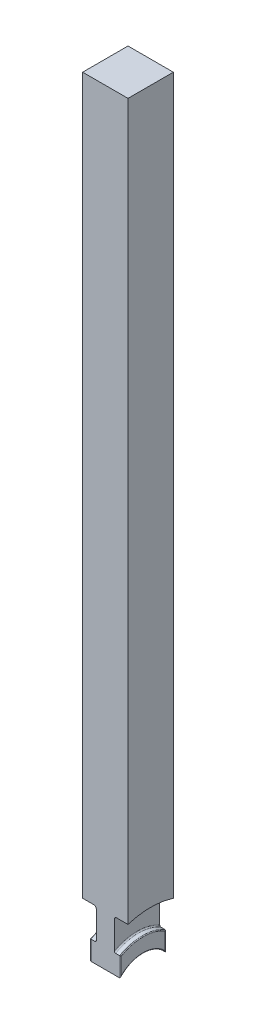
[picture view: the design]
ISO-10303-21;
HEADER;
FILE_DESCRIPTION(('STEP AP214'),'2;1');
FILE_NAME('part.step','',(''),(''),'','','');
FILE_SCHEMA(('AUTOMOTIVE_DESIGN { 1 0 10303 214 1 1 1 1 }'));
ENDSEC;
DATA;
#1=APPLICATION_CONTEXT('core data for automotive mechanical design processes');
#2=APPLICATION_PROTOCOL_DEFINITION('international standard','automotive_design',2000,#1);
#3=PRODUCT_CONTEXT('',#1,'mechanical');
#4=PRODUCT('Part','Part','',(#3));
#5=PRODUCT_RELATED_PRODUCT_CATEGORY('part','',(#4));
#6=PRODUCT_DEFINITION_FORMATION('','',#4);
#7=PRODUCT_DEFINITION_CONTEXT('part definition',#1,'design');
#8=PRODUCT_DEFINITION('design','',#6,#7);
#9=PRODUCT_DEFINITION_SHAPE('','',#8);
#10=(LENGTH_UNIT() NAMED_UNIT(*) SI_UNIT(.MILLI.,.METRE.));
#11=(NAMED_UNIT(*) PLANE_ANGLE_UNIT() SI_UNIT($,.RADIAN.));
#12=(NAMED_UNIT(*) SI_UNIT($,.STERADIAN.) SOLID_ANGLE_UNIT());
#13=UNCERTAINTY_MEASURE_WITH_UNIT(LENGTH_MEASURE(1.E-05),#10,'distance_accuracy_value','');
#14=(GEOMETRIC_REPRESENTATION_CONTEXT(3) GLOBAL_UNCERTAINTY_ASSIGNED_CONTEXT((#13)) GLOBAL_UNIT_ASSIGNED_CONTEXT((#10,
#11,#12)) REPRESENTATION_CONTEXT('',''));
#15=CARTESIAN_POINT('',(0.,0.,0.));
#16=DIRECTION('',(0.,0.,1.));
#17=DIRECTION('',(1.,0.,0.));
#18=AXIS2_PLACEMENT_3D('',#15,#16,#17);
#19=CARTESIAN_POINT('',(7.5,260.,7.5));
#20=DIRECTION('',(0.,0.,-1.));
#21=DIRECTION('',(0.,1.,0.));
#22=AXIS2_PLACEMENT_3D('',#19,#20,#21);
#23=PLANE('',#22);
#24=DIRECTION('',(-1.,0.,0.));
#25=VECTOR('',#24,1.);
#26=CARTESIAN_POINT('',(-8.84822894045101,12.9903810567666,7.49999999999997));
#27=LINE('',#26,#25);
#28=CARTESIAN_POINT('',(-4.75,12.9903810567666,7.49999999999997));
#29=VERTEX_POINT('',#28);
#30=CARTESIAN_POINT('',(-3.381,12.9903810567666,7.49999999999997));
#31=VERTEX_POINT('',#30);
#32=EDGE_CURVE('E731',#29,#31,#27,.F.);
#33=ORIENTED_EDGE('',*,*,#32,.F.);
#34=DIRECTION('',(0.,1.,0.));
#35=VECTOR('',#34,1.);
#36=CARTESIAN_POINT('',(-4.75000000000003,260.,7.5));
#37=LINE('',#36,#35);
#38=CARTESIAN_POINT('',(-4.75,6.61437827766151,7.49999999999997));
#39=VERTEX_POINT('',#38);
#40=EDGE_CURVE('E442',#29,#39,#37,.F.);
#41=ORIENTED_EDGE('',*,*,#40,.T.);
#42=DIRECTION('',(1.,0.,0.));
#43=VECTOR('',#42,1.);
#44=CARTESIAN_POINT('',(-7.5,6.61437827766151,7.49999999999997));
#45=LINE('',#44,#43);
#46=CARTESIAN_POINT('',(4.75,6.61437827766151,7.49999999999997));
#47=VERTEX_POINT('',#46);
#48=EDGE_CURVE('E212',#39,#47,#45,.T.);
#49=ORIENTED_EDGE('',*,*,#48,.T.);
#50=DIRECTION('',(0.,-1.,0.));
#51=VECTOR('',#50,1.);
#52=CARTESIAN_POINT('',(4.74999999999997,260.,7.5));
#53=LINE('',#52,#51);
#54=CARTESIAN_POINT('',(4.75,12.9903810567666,7.49999999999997));
#55=VERTEX_POINT('',#54);
#56=EDGE_CURVE('E440',#47,#55,#53,.F.);
#57=ORIENTED_EDGE('',*,*,#56,.T.);
#58=DIRECTION('',(-1.,0.,0.));
#59=VECTOR('',#58,1.);
#60=CARTESIAN_POINT('',(-8.84822894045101,12.9903810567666,7.49999999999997));
#61=LINE('',#60,#59);
#62=CARTESIAN_POINT('',(3.381,12.9903810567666,7.49999999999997));
#63=VERTEX_POINT('',#62);
#64=EDGE_CURVE('E734',#63,#55,#61,.F.);
#65=ORIENTED_EDGE('',*,*,#64,.F.);
#66=CARTESIAN_POINT('',(3.381,12.9903810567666,7.49999999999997));
#67=CARTESIAN_POINT('',(3.36159348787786,12.990351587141,7.49999999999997));
#68=CARTESIAN_POINT('',(3.34220939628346,12.9920910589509,7.49999999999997));
#69=CARTESIAN_POINT('',(3.30411089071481,12.9988686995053,7.49999999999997));
#70=CARTESIAN_POINT('',(3.28539391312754,13.0038923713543,7.49999999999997));
#71=CARTESIAN_POINT('',(3.24909102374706,13.0169971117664,7.49999999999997));
#72=CARTESIAN_POINT('',(3.23150411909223,13.0250754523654,7.49999999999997));
#73=CARTESIAN_POINT('',(3.19783116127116,13.0439266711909,7.49999999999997));
#74=CARTESIAN_POINT('',(3.18174642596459,13.054701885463,7.49999999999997));
#75=CARTESIAN_POINT('',(3.15058262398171,13.0791681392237,7.49999999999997));
#76=CARTESIAN_POINT('',(3.1356009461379,13.0929827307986,7.49999999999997));
#77=CARTESIAN_POINT('',(3.10785285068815,13.1226713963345,7.49999999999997));
#78=CARTESIAN_POINT('',(3.09508691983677,13.1385459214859,7.49999999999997));
#79=CARTESIAN_POINT('',(3.07041818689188,13.1740413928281,7.49999999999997));
#80=CARTESIAN_POINT('',(3.05883169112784,13.1938820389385,7.49999999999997));
#81=CARTESIAN_POINT('',(3.03871875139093,13.235070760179,7.49999999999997));
#82=CARTESIAN_POINT('',(3.03019562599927,13.2564204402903,7.49999999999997));
#83=CARTESIAN_POINT('',(3.01549657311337,13.3025258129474,7.49999999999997));
#84=CARTESIAN_POINT('',(3.00968374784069,13.3273972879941,7.49999999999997));
#85=CARTESIAN_POINT('',(3.00193752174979,13.3776913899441,7.49999999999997));
#86=CARTESIAN_POINT('',(2.99999691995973,13.4031129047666,7.49999999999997));
#87=CARTESIAN_POINT('',(3.,13.428520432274,7.49999999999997));
#88=B_SPLINE_CURVE_WITH_KNOTS('',3,(#66,#67,#68,#69,#70,#71,#72,#73,#74,#75,#76,#77,#78,#79,#80,
#81,#82,#83,#84,#85,#86,#87),.UNSPECIFIED.,.F.,.F.,(4,2,2,2,2,2,2,2,2,2,4),(0.,
0.0581065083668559,0.115958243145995,0.173758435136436,0.231608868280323,0.292501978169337,
0.353408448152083,0.422061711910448,0.490789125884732,0.567105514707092,0.643279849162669),.UNSPECIFIED.);
#89=CARTESIAN_POINT('',(3.,13.428520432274,7.49999999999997));
#90=VERTEX_POINT('',#89);
#91=EDGE_CURVE('E312',#63,#90,#88,.T.);
#92=ORIENTED_EDGE('',*,*,#91,.T.);
#93=DIRECTION('',(0.,-1.,0.));
#94=VECTOR('',#93,1.);
#95=CARTESIAN_POINT('',(3.,260.,7.5));
#96=LINE('',#95,#94);
#97=CARTESIAN_POINT('',(3.,22.5220479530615,7.49999999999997));
#98=VERTEX_POINT('',#97);
#99=EDGE_CURVE('E464',#98,#90,#96,.T.);
#100=ORIENTED_EDGE('',*,*,#99,.F.);
#101=CARTESIAN_POINT('',(3.,22.5220479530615,7.49999999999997));
#102=CARTESIAN_POINT('',(2.99997149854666,22.5689651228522,7.49999999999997));
#103=CARTESIAN_POINT('',(3.00389939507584,22.6158879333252,7.49999999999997));
#104=CARTESIAN_POINT('',(3.01949238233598,22.7084725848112,7.49999999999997));
#105=CARTESIAN_POINT('',(3.03116447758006,22.754133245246,7.49999999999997));
#106=CARTESIAN_POINT('',(3.06208646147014,22.8428798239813,7.49999999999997));
#107=CARTESIAN_POINT('',(3.08134457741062,22.885962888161,7.49999999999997));
#108=CARTESIAN_POINT('',(3.12700930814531,22.9681343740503,7.49999999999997));
#109=CARTESIAN_POINT('',(3.15341113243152,23.0072254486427,7.49999999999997));
#110=CARTESIAN_POINT('',(3.21190757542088,23.0791064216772,7.49999999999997));
#111=CARTESIAN_POINT('',(3.24382440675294,23.1120407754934,7.49999999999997));
#112=CARTESIAN_POINT('',(3.31300016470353,23.171752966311,7.49999999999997));
#113=CARTESIAN_POINT('',(3.35025938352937,23.1985304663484,7.49999999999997));
#114=CARTESIAN_POINT('',(3.42707441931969,23.2437458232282,7.49999999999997));
#115=CARTESIAN_POINT('',(3.46642748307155,23.262528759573,7.49999999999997));
#116=CARTESIAN_POINT('',(3.54780361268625,23.2928652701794,7.49999999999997));
#117=CARTESIAN_POINT('',(3.58982304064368,23.3044284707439,7.49999999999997));
#118=CARTESIAN_POINT('',(3.65386676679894,23.3160362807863,7.49999999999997));
#119=CARTESIAN_POINT('',(3.67540624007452,23.3189494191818,7.49999999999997));
#120=CARTESIAN_POINT('',(3.71862671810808,23.322833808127,7.49999999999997));
#121=CARTESIAN_POINT('',(3.74030745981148,23.323807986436,7.49999999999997));
#122=CARTESIAN_POINT('',(3.76199999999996,23.3238075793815,7.49999999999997));
#123=B_SPLINE_CURVE_WITH_KNOTS('',3,(#101,#102,#103,#104,#105,#106,#107,#108,#109,#110,#111,
#112,#113,#114,#115,#116,#117,#118,#119,#120,#121,#122),.UNSPECIFIED.,.F.,.F.,(4,2,2,2,2,2,2,2,
2,2,4),(0.,0.140598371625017,0.281324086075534,0.422202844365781,0.562987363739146,
0.699875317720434,0.836770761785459,0.966940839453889,1.09693698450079,1.16206792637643,
1.22710044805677),.UNSPECIFIED.);
#124=CARTESIAN_POINT('',(3.762,23.3238075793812,7.49999999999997));
#125=VERTEX_POINT('',#124);
#126=EDGE_CURVE('E277',#98,#125,#123,.T.);
#127=ORIENTED_EDGE('',*,*,#126,.T.);
#128=DIRECTION('',(-1.,0.,0.));
#129=VECTOR('',#128,1.);
#130=CARTESIAN_POINT('',(-8.84822894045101,23.3238075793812,7.49999999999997));
#131=LINE('',#130,#129);
#132=CARTESIAN_POINT('',(7.50000000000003,23.3238075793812,7.49999999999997));
#133=VERTEX_POINT('',#132);
#134=EDGE_CURVE('E741',#133,#125,#131,.T.);
#135=ORIENTED_EDGE('',*,*,#134,.F.);
#136=DIRECTION('',(0.,-1.,0.));
#137=VECTOR('',#136,1.);
#138=CARTESIAN_POINT('',(7.5,260.,7.5));
#139=LINE('',#138,#137);
#140=CARTESIAN_POINT('',(7.5,260.,7.5));
#141=VERTEX_POINT('',#140);
#142=EDGE_CURVE('E470',#141,#133,#139,.T.);
#143=ORIENTED_EDGE('',*,*,#142,.F.);
#144=DIRECTION('',(-1.,0.,0.));
#145=VECTOR('',#144,1.);
#146=CARTESIAN_POINT('',(7.5,260.,7.5));
#147=LINE('',#146,#145);
#148=CARTESIAN_POINT('',(-7.5,260.,7.5));
#149=VERTEX_POINT('',#148);
#150=EDGE_CURVE('E206',#141,#149,#147,.T.);
#151=ORIENTED_EDGE('',*,*,#150,.T.);
#152=DIRECTION('',(0.,-1.,0.));
#153=VECTOR('',#152,1.);
#154=CARTESIAN_POINT('',(-7.5,260.,7.5));
#155=LINE('',#154,#153);
#156=CARTESIAN_POINT('',(-7.50000000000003,23.3238075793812,7.49999999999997));
#157=VERTEX_POINT('',#156);
#158=EDGE_CURVE('E198',#149,#157,#155,.T.);
#159=ORIENTED_EDGE('',*,*,#158,.T.);
#160=DIRECTION('',(-1.,0.,0.));
#161=VECTOR('',#160,1.);
#162=CARTESIAN_POINT('',(-8.84822894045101,23.3238075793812,7.49999999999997));
#163=LINE('',#162,#161);
#164=CARTESIAN_POINT('',(-3.762,23.3238075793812,7.49999999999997));
#165=VERTEX_POINT('',#164);
#166=EDGE_CURVE('E179',#165,#157,#163,.T.);
#167=ORIENTED_EDGE('',*,*,#166,.F.);
#168=CARTESIAN_POINT('',(-3.762,23.3238075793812,7.49999999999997));
#169=CARTESIAN_POINT('',(-3.72062832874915,23.3238520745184,7.49999999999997));
#170=CARTESIAN_POINT('',(-3.67927922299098,23.3202713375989,7.49999999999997));
#171=CARTESIAN_POINT('',(-3.59785901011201,23.3062018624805,7.49999999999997));
#172=CARTESIAN_POINT('',(-3.55778541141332,23.2957275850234,7.49999999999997));
#173=CARTESIAN_POINT('',(-3.47996559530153,23.2682105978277,7.49999999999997));
#174=CARTESIAN_POINT('',(-3.44221943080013,23.2511677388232,7.49999999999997));
#175=CARTESIAN_POINT('',(-3.37004313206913,23.2111093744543,7.49999999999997));
#176=CARTESIAN_POINT('',(-3.33561363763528,23.1880927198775,7.49999999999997));
#177=CARTESIAN_POINT('',(-3.27027005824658,23.1363093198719,7.49999999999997));
#178=CARTESIAN_POINT('',(-3.23943952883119,23.107437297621,7.49999999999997));
#179=CARTESIAN_POINT('',(-3.18280382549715,23.0451270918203,7.49999999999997));
#180=CARTESIAN_POINT('',(-3.15699985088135,23.0116878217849,7.49999999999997));
#181=CARTESIAN_POINT('',(-3.10989501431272,22.9395756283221,7.49999999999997));
#182=CARTESIAN_POINT('',(-3.08885347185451,22.9007334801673,7.49999999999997));
#183=CARTESIAN_POINT('',(-3.05325919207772,22.8201786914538,7.49999999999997));
#184=CARTESIAN_POINT('',(-3.03870727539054,22.7784656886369,7.49999999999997));
#185=CARTESIAN_POINT('',(-3.01837577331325,22.7009990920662,7.49999999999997));
#186=CARTESIAN_POINT('',(-3.01148586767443,22.6655314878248,7.49999999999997));
#187=CARTESIAN_POINT('',(-3.00229780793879,22.5940601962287,7.49999999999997));
#188=CARTESIAN_POINT('',(-2.99999277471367,22.5580573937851,7.49999999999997));
#189=CARTESIAN_POINT('',(-3.,22.5220479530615,7.49999999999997));
#190=B_SPLINE_CURVE_WITH_KNOTS('',3,(#168,#169,#170,#171,#172,#173,#174,#175,#176,#177,#178,
#179,#180,#181,#182,#183,#184,#185,#186,#187,#188,#189),.UNSPECIFIED.,.F.,.F.,(4,2,2,2,2,2,2,2,
2,2,4),(0.,0.12392580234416,0.247592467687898,0.371261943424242,0.49495522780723,
0.621109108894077,0.747293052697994,0.879236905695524,1.01119743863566,1.11930081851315,
1.2272418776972),.UNSPECIFIED.);
#191=CARTESIAN_POINT('',(-3.,22.5220479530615,7.49999999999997));
#192=VERTEX_POINT('',#191);
#193=EDGE_CURVE('E243',#165,#192,#190,.T.);
#194=ORIENTED_EDGE('',*,*,#193,.T.);
#195=DIRECTION('',(0.,1.,0.));
#196=VECTOR('',#195,1.);
#197=CARTESIAN_POINT('',(-3.,260.,7.5));
#198=LINE('',#197,#196);
#199=CARTESIAN_POINT('',(-3.,13.428520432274,7.49999999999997));
#200=VERTEX_POINT('',#199);
#201=EDGE_CURVE('E732',#200,#192,#198,.T.);
#202=ORIENTED_EDGE('',*,*,#201,.F.);
#203=CARTESIAN_POINT('',(-3.,13.428520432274,7.49999999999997));
#204=CARTESIAN_POINT('',(-2.99998773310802,13.3960473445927,7.49999999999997));
#205=CARTESIAN_POINT('',(-3.00316588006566,13.3635248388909,7.49999999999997));
#206=CARTESIAN_POINT('',(-3.01585357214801,13.2995632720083,7.49999999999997));
#207=CARTESIAN_POINT('',(-3.02539701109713,13.2681309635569,7.49999999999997));
#208=CARTESIAN_POINT('',(-3.04884901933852,13.2124568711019,7.49999999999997));
#209=CARTESIAN_POINT('',(-3.06188078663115,13.1878460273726,7.49999999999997));
#210=CARTESIAN_POINT('',(-3.09231245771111,13.1415402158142,7.49999999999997));
#211=CARTESIAN_POINT('',(-3.10970093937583,13.1198378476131,7.49999999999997));
#212=CARTESIAN_POINT('',(-3.14655915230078,13.0824144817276,7.49999999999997));
#213=CARTESIAN_POINT('',(-3.16563766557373,13.0663097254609,7.49999999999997));
#214=CARTESIAN_POINT('',(-3.20659393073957,13.0381967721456,7.49999999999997));
#215=CARTESIAN_POINT('',(-3.22846666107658,13.0261813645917,7.49999999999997));
#216=CARTESIAN_POINT('',(-3.2717749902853,13.0081040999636,7.49999999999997));
#217=CARTESIAN_POINT('',(-3.2929987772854,13.0015363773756,7.49999999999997));
#218=CARTESIAN_POINT('',(-3.33646159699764,12.9926369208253,7.49999999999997));
#219=CARTESIAN_POINT('',(-3.35870658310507,12.9903344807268,7.49999999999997));
#220=CARTESIAN_POINT('',(-3.381,12.9903810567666,7.49999999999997));
#221=B_SPLINE_CURVE_WITH_KNOTS('',3,(#203,#204,#205,#206,#207,#208,#209,#210,#211,#212,#213,
#214,#215,#216,#217,#218,#219,#220),.UNSPECIFIED.,.F.,.F.,(4,2,2,2,2,2,2,2,4),(0.,
0.0973546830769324,0.195231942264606,0.278328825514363,0.36121009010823,0.435666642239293,
0.509991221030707,0.576221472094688,0.642904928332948),.UNSPECIFIED.);
#222=EDGE_CURVE('E292',#200,#31,#221,.T.);
#223=ORIENTED_EDGE('',*,*,#222,.T.);
#224=EDGE_LOOP('',(#33,#41,#49,#57,#65,#92,#100,#127,#135,#143,#151,#159,#167,#194,#202,#223));
#225=FACE_BOUND('',#224,.T.);
#226=ADVANCED_FACE('F37',(#225),#23,.F.);
#227=CARTESIAN_POINT('',(7.5,260.,-7.5));
#228=DIRECTION('',(0.,0.,1.));
#229=DIRECTION('',(0.,-1.,0.));
#230=AXIS2_PLACEMENT_3D('',#227,#228,#229);
#231=PLANE('',#230);
#232=DIRECTION('',(1.,0.,0.));
#233=VECTOR('',#232,1.);
#234=CARTESIAN_POINT('',(-7.5,6.61437827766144,-7.50000000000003));
#235=LINE('',#234,#233);
#236=CARTESIAN_POINT('',(4.75,6.61437827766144,-7.50000000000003));
#237=VERTEX_POINT('',#236);
#238=CARTESIAN_POINT('',(-4.75,6.61437827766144,-7.50000000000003));
#239=VERTEX_POINT('',#238);
#240=EDGE_CURVE('E462',#237,#239,#235,.F.);
#241=ORIENTED_EDGE('',*,*,#240,.T.);
#242=DIRECTION('',(0.,1.,0.));
#243=VECTOR('',#242,1.);
#244=CARTESIAN_POINT('',(-4.75000000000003,260.,-7.5));
#245=LINE('',#244,#243);
#246=CARTESIAN_POINT('',(-4.75,12.9903810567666,-7.50000000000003));
#247=VERTEX_POINT('',#246);
#248=EDGE_CURVE('E432',#239,#247,#245,.T.);
#249=ORIENTED_EDGE('',*,*,#248,.T.);
#250=DIRECTION('',(-1.,0.,0.));
#251=VECTOR('',#250,1.);
#252=CARTESIAN_POINT('',(-8.84822894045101,12.9903810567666,-7.50000000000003));
#253=LINE('',#252,#251);
#254=CARTESIAN_POINT('',(-3.381,12.9903810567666,-7.50000000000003));
#255=VERTEX_POINT('',#254);
#256=EDGE_CURVE('E747',#255,#247,#253,.T.);
#257=ORIENTED_EDGE('',*,*,#256,.F.);
#258=CARTESIAN_POINT('',(-3.381,12.9903810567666,-7.50000000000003));
#259=CARTESIAN_POINT('',(-3.36159348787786,12.9903515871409,-7.50000000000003));
#260=CARTESIAN_POINT('',(-3.34220939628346,12.9920910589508,-7.50000000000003));
#261=CARTESIAN_POINT('',(-3.30411089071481,12.9988686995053,-7.50000000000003));
#262=CARTESIAN_POINT('',(-3.28539391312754,13.0038923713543,-7.50000000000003));
#263=CARTESIAN_POINT('',(-3.24909102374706,13.0169971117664,-7.50000000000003));
#264=CARTESIAN_POINT('',(-3.23150411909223,13.0250754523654,-7.50000000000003));
#265=CARTESIAN_POINT('',(-3.19783116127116,13.0439266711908,-7.50000000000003));
#266=CARTESIAN_POINT('',(-3.18174642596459,13.054701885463,-7.50000000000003));
#267=CARTESIAN_POINT('',(-3.1505826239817,13.0791681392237,-7.50000000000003));
#268=CARTESIAN_POINT('',(-3.13560094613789,13.0929827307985,-7.50000000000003));
#269=CARTESIAN_POINT('',(-3.10785285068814,13.1226713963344,-7.50000000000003));
#270=CARTESIAN_POINT('',(-3.09508691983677,13.1385459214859,-7.50000000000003));
#271=CARTESIAN_POINT('',(-3.07041818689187,13.174041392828,-7.50000000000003));
#272=CARTESIAN_POINT('',(-3.05883169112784,13.1938820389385,-7.50000000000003));
#273=CARTESIAN_POINT('',(-3.03871875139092,13.2350707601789,-7.50000000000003));
#274=CARTESIAN_POINT('',(-3.03019562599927,13.2564204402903,-7.50000000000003));
#275=CARTESIAN_POINT('',(-3.01549657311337,13.3025258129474,-7.50000000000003));
#276=CARTESIAN_POINT('',(-3.00968374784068,13.327397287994,-7.50000000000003));
#277=CARTESIAN_POINT('',(-3.00193752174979,13.3776913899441,-7.50000000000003));
#278=CARTESIAN_POINT('',(-2.99999691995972,13.4031129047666,-7.50000000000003));
#279=CARTESIAN_POINT('',(-3.,13.428520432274,-7.50000000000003));
#280=B_SPLINE_CURVE_WITH_KNOTS('',3,(#258,#259,#260,#261,#262,#263,#264,#265,#266,#267,#268,
#269,#270,#271,#272,#273,#274,#275,#276,#277,#278,#279),.UNSPECIFIED.,.F.,.F.,(4,2,2,2,2,2,2,2,
2,2,4),(0.,0.058106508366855,0.115958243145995,0.173758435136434,0.231608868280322,
0.292501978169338,0.353408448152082,0.422061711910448,0.490789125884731,0.567105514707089,
0.643279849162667),.UNSPECIFIED.);
#281=CARTESIAN_POINT('',(-3.,13.428520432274,-7.50000000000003));
#282=VERTEX_POINT('',#281);
#283=EDGE_CURVE('E301',#255,#282,#280,.T.);
#284=ORIENTED_EDGE('',*,*,#283,.T.);
#285=DIRECTION('',(0.,-1.,0.));
#286=VECTOR('',#285,1.);
#287=CARTESIAN_POINT('',(-3.,260.,-7.5));
#288=LINE('',#287,#286);
#289=CARTESIAN_POINT('',(-3.,22.5220479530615,-7.50000000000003));
#290=VERTEX_POINT('',#289);
#291=EDGE_CURVE('E221',#290,#282,#288,.T.);
#292=ORIENTED_EDGE('',*,*,#291,.F.);
#293=CARTESIAN_POINT('',(-3.,22.5220479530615,-7.50000000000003));
#294=CARTESIAN_POINT('',(-2.99997149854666,22.5689651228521,-7.50000000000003));
#295=CARTESIAN_POINT('',(-3.00389939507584,22.6158879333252,-7.50000000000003));
#296=CARTESIAN_POINT('',(-3.01949238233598,22.7084725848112,-7.50000000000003));
#297=CARTESIAN_POINT('',(-3.03116447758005,22.754133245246,-7.50000000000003));
#298=CARTESIAN_POINT('',(-3.06208646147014,22.8428798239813,-7.50000000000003));
#299=CARTESIAN_POINT('',(-3.08134457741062,22.8859628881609,-7.50000000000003));
#300=CARTESIAN_POINT('',(-3.12700930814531,22.9681343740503,-7.50000000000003));
#301=CARTESIAN_POINT('',(-3.15341113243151,23.0072254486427,-7.50000000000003));
#302=CARTESIAN_POINT('',(-3.21190757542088,23.0791064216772,-7.50000000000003));
#303=CARTESIAN_POINT('',(-3.24382440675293,23.1120407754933,-7.50000000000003));
#304=CARTESIAN_POINT('',(-3.31300016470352,23.1717529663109,-7.50000000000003));
#305=CARTESIAN_POINT('',(-3.35025938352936,23.1985304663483,-7.50000000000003));
#306=CARTESIAN_POINT('',(-3.42707441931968,23.2437458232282,-7.50000000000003));
#307=CARTESIAN_POINT('',(-3.46642748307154,23.262528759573,-7.50000000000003));
#308=CARTESIAN_POINT('',(-3.54780361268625,23.2928652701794,-7.50000000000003));
#309=CARTESIAN_POINT('',(-3.58982304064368,23.3044284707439,-7.50000000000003));
#310=CARTESIAN_POINT('',(-3.65386676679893,23.3160362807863,-7.50000000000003));
#311=CARTESIAN_POINT('',(-3.67540624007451,23.3189494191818,-7.50000000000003));
#312=CARTESIAN_POINT('',(-3.71862671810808,23.322833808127,-7.50000000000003));
#313=CARTESIAN_POINT('',(-3.74030745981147,23.323807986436,-7.50000000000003));
#314=CARTESIAN_POINT('',(-3.76199999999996,23.3238075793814,-7.50000000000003));
#315=B_SPLINE_CURVE_WITH_KNOTS('',3,(#293,#294,#295,#296,#297,#298,#299,#300,#301,#302,#303,
#304,#305,#306,#307,#308,#309,#310,#311,#312,#313,#314),.UNSPECIFIED.,.F.,.F.,(4,2,2,2,2,2,2,2,
2,2,4),(0.,0.140598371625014,0.281324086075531,0.422202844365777,0.562987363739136,
0.699875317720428,0.836770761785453,0.966940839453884,1.09693698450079,1.16206792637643,
1.22710044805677),.UNSPECIFIED.);
#316=CARTESIAN_POINT('',(-3.762,23.3238075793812,-7.50000000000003));
#317=VERTEX_POINT('',#316);
#318=EDGE_CURVE('E235',#290,#317,#315,.T.);
#319=ORIENTED_EDGE('',*,*,#318,.T.);
#320=DIRECTION('',(-1.,0.,0.));
#321=VECTOR('',#320,1.);
#322=CARTESIAN_POINT('',(-8.84822894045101,23.3238075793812,-7.50000000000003));
#323=LINE('',#322,#321);
#324=CARTESIAN_POINT('',(-7.50000000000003,23.3238075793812,-7.50000000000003));
#325=VERTEX_POINT('',#324);
#326=EDGE_CURVE('E192',#325,#317,#323,.F.);
#327=ORIENTED_EDGE('',*,*,#326,.F.);
#328=DIRECTION('',(0.,1.,0.));
#329=VECTOR('',#328,1.);
#330=CARTESIAN_POINT('',(-7.5,260.,-7.5));
#331=LINE('',#330,#329);
#332=CARTESIAN_POINT('',(-7.5,260.,-7.5));
#333=VERTEX_POINT('',#332);
#334=EDGE_CURVE('E200',#325,#333,#331,.T.);
#335=ORIENTED_EDGE('',*,*,#334,.T.);
#336=DIRECTION('',(-1.,0.,0.));
#337=VECTOR('',#336,1.);
#338=CARTESIAN_POINT('',(7.5,260.,-7.5));
#339=LINE('',#338,#337);
#340=CARTESIAN_POINT('',(7.5,260.,-7.5));
#341=VERTEX_POINT('',#340);
#342=EDGE_CURVE('E216',#341,#333,#339,.T.);
#343=ORIENTED_EDGE('',*,*,#342,.F.);
#344=DIRECTION('',(0.,1.,0.));
#345=VECTOR('',#344,1.);
#346=CARTESIAN_POINT('',(7.5,260.,-7.5));
#347=LINE('',#346,#345);
#348=CARTESIAN_POINT('',(7.5,23.3238075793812,-7.50000000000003));
#349=VERTEX_POINT('',#348);
#350=EDGE_CURVE('E219',#349,#341,#347,.T.);
#351=ORIENTED_EDGE('',*,*,#350,.F.);
#352=DIRECTION('',(-1.,0.,0.));
#353=VECTOR('',#352,1.);
#354=CARTESIAN_POINT('',(-8.84822894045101,23.3238075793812,-7.50000000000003));
#355=LINE('',#354,#353);
#356=CARTESIAN_POINT('',(3.762,23.3238075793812,-7.50000000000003));
#357=VERTEX_POINT('',#356);
#358=EDGE_CURVE('E191',#357,#349,#355,.F.);
#359=ORIENTED_EDGE('',*,*,#358,.F.);
#360=CARTESIAN_POINT('',(3.762,23.3238075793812,-7.50000000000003));
#361=CARTESIAN_POINT('',(3.72062832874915,23.3238520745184,-7.50000000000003));
#362=CARTESIAN_POINT('',(3.67927922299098,23.3202713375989,-7.50000000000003));
#363=CARTESIAN_POINT('',(3.59785901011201,23.3062018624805,-7.50000000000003));
#364=CARTESIAN_POINT('',(3.55778541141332,23.2957275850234,-7.50000000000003));
#365=CARTESIAN_POINT('',(3.47996559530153,23.2682105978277,-7.50000000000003));
#366=CARTESIAN_POINT('',(3.44221943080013,23.2511677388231,-7.50000000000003));
#367=CARTESIAN_POINT('',(3.37004313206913,23.2111093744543,-7.50000000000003));
#368=CARTESIAN_POINT('',(3.33561363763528,23.1880927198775,-7.50000000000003));
#369=CARTESIAN_POINT('',(3.27027005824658,23.1363093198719,-7.50000000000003));
#370=CARTESIAN_POINT('',(3.2394395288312,23.107437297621,-7.50000000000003));
#371=CARTESIAN_POINT('',(3.18280382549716,23.0451270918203,-7.50000000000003));
#372=CARTESIAN_POINT('',(3.15699985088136,23.0116878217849,-7.50000000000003));
#373=CARTESIAN_POINT('',(3.10989501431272,22.9395756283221,-7.50000000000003));
#374=CARTESIAN_POINT('',(3.08885347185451,22.9007334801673,-7.50000000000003));
#375=CARTESIAN_POINT('',(3.05325919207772,22.8201786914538,-7.50000000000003));
#376=CARTESIAN_POINT('',(3.03870727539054,22.7784656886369,-7.50000000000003));
#377=CARTESIAN_POINT('',(3.01837577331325,22.7009990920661,-7.50000000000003));
#378=CARTESIAN_POINT('',(3.01148586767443,22.6655314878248,-7.50000000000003));
#379=CARTESIAN_POINT('',(3.00229780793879,22.5940601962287,-7.50000000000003));
#380=CARTESIAN_POINT('',(2.99999277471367,22.5580573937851,-7.50000000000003));
#381=CARTESIAN_POINT('',(3.,22.5220479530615,-7.50000000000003));
#382=B_SPLINE_CURVE_WITH_KNOTS('',3,(#360,#361,#362,#363,#364,#365,#366,#367,#368,#369,#370,
#371,#372,#373,#374,#375,#376,#377,#378,#379,#380,#381),.UNSPECIFIED.,.F.,.F.,(4,2,2,2,2,2,2,2,
2,2,4),(0.,0.123925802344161,0.247592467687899,0.371261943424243,0.494955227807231,
0.621109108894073,0.747293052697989,0.879236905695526,1.01119743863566,1.11930081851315,
1.2272418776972),.UNSPECIFIED.);
#383=CARTESIAN_POINT('',(3.,22.5220479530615,-7.50000000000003));
#384=VERTEX_POINT('',#383);
#385=EDGE_CURVE('E271',#357,#384,#382,.T.);
#386=ORIENTED_EDGE('',*,*,#385,.T.);
#387=DIRECTION('',(0.,1.,0.));
#388=VECTOR('',#387,1.);
#389=CARTESIAN_POINT('',(3.,260.,-7.5));
#390=LINE('',#389,#388);
#391=CARTESIAN_POINT('',(3.,13.428520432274,-7.50000000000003));
#392=VERTEX_POINT('',#391);
#393=EDGE_CURVE('E224',#392,#384,#390,.T.);
#394=ORIENTED_EDGE('',*,*,#393,.F.);
#395=CARTESIAN_POINT('',(3.,13.428520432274,-7.50000000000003));
#396=CARTESIAN_POINT('',(2.99998773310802,13.3960473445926,-7.50000000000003));
#397=CARTESIAN_POINT('',(3.00316588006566,13.3635248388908,-7.50000000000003));
#398=CARTESIAN_POINT('',(3.01585357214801,13.2995632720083,-7.50000000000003));
#399=CARTESIAN_POINT('',(3.02539701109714,13.2681309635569,-7.50000000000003));
#400=CARTESIAN_POINT('',(3.04884901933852,13.2124568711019,-7.50000000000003));
#401=CARTESIAN_POINT('',(3.06188078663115,13.1878460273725,-7.50000000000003));
#402=CARTESIAN_POINT('',(3.09231245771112,13.1415402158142,-7.50000000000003));
#403=CARTESIAN_POINT('',(3.10970093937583,13.1198378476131,-7.50000000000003));
#404=CARTESIAN_POINT('',(3.14655915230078,13.0824144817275,-7.50000000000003));
#405=CARTESIAN_POINT('',(3.16563766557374,13.0663097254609,-7.50000000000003));
#406=CARTESIAN_POINT('',(3.20659393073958,13.0381967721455,-7.50000000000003));
#407=CARTESIAN_POINT('',(3.22846666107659,13.0261813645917,-7.50000000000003));
#408=CARTESIAN_POINT('',(3.27177499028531,13.0081040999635,-7.50000000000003));
#409=CARTESIAN_POINT('',(3.2929987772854,13.0015363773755,-7.50000000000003));
#410=CARTESIAN_POINT('',(3.33646159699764,12.9926369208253,-7.50000000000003));
#411=CARTESIAN_POINT('',(3.35870658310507,12.9903344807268,-7.50000000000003));
#412=CARTESIAN_POINT('',(3.381,12.9903810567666,-7.50000000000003));
#413=B_SPLINE_CURVE_WITH_KNOTS('',3,(#395,#396,#397,#398,#399,#400,#401,#402,#403,#404,#405,
#406,#407,#408,#409,#410,#411,#412),.UNSPECIFIED.,.F.,.F.,(4,2,2,2,2,2,2,2,4),(0.,
0.0973546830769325,0.195231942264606,0.278328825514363,0.361210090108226,0.435666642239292,
0.509991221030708,0.576221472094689,0.642904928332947),.UNSPECIFIED.);
#414=CARTESIAN_POINT('',(3.381,12.9903810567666,-7.50000000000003));
#415=VERTEX_POINT('',#414);
#416=EDGE_CURVE('E300',#392,#415,#413,.T.);
#417=ORIENTED_EDGE('',*,*,#416,.T.);
#418=DIRECTION('',(-1.,0.,0.));
#419=VECTOR('',#418,1.);
#420=CARTESIAN_POINT('',(-8.84822894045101,12.9903810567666,-7.50000000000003));
#421=LINE('',#420,#419);
#422=CARTESIAN_POINT('',(4.75,12.9903810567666,-7.50000000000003));
#423=VERTEX_POINT('',#422);
#424=EDGE_CURVE('E737',#423,#415,#421,.T.);
#425=ORIENTED_EDGE('',*,*,#424,.F.);
#426=DIRECTION('',(0.,-1.,0.));
#427=VECTOR('',#426,1.);
#428=CARTESIAN_POINT('',(4.74999999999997,260.,-7.5));
#429=LINE('',#428,#427);
#430=EDGE_CURVE('E407',#423,#237,#429,.T.);
#431=ORIENTED_EDGE('',*,*,#430,.T.);
#432=EDGE_LOOP('',(#241,#249,#257,#284,#292,#319,#327,#335,#343,#351,#359,#386,#394,#417,#425,#431));
#433=FACE_BOUND('',#432,.T.);
#434=ADVANCED_FACE('F250',(#433),#231,.F.);
#435=CARTESIAN_POINT('',(-7.5,0.,0.));
#436=DIRECTION('',(-1.,0.,0.));
#437=DIRECTION('',(0.,0.,1.));
#438=AXIS2_PLACEMENT_3D('',#435,#436,#437);
#439=PLANE('',#438);
#440=ORIENTED_EDGE('',*,*,#334,.F.);
#441=CARTESIAN_POINT('',(-7.50000000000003,0.,0.));
#442=DIRECTION('',(-1.,0.,0.));
#443=DIRECTION('',(0.,0.,1.));
#444=AXIS2_PLACEMENT_3D('',#441,#442,#443);
#445=CIRCLE('',#444,24.5);
#446=EDGE_CURVE('E183',#157,#325,#445,.T.);
#447=ORIENTED_EDGE('',*,*,#446,.F.);
#448=ORIENTED_EDGE('',*,*,#158,.F.);
#449=DIRECTION('',(0.,0.,1.));
#450=VECTOR('',#449,1.);
#451=CARTESIAN_POINT('',(-7.5,260.,7.5));
#452=LINE('',#451,#450);
#453=EDGE_CURVE('E208',#333,#149,#452,.T.);
#454=ORIENTED_EDGE('',*,*,#453,.F.);
#455=EDGE_LOOP('',(#440,#447,#448,#454));
#456=FACE_BOUND('',#455,.T.);
#457=ADVANCED_FACE('F196',(#456),#439,.T.);
#458=CARTESIAN_POINT('',(7.5,260.,7.5));
#459=DIRECTION('',(0.,-1.,0.));
#460=DIRECTION('',(0.,0.,-1.));
#461=AXIS2_PLACEMENT_3D('',#458,#459,#460);
#462=PLANE('',#461);
#463=ORIENTED_EDGE('',*,*,#453,.T.);
#464=ORIENTED_EDGE('',*,*,#150,.F.);
#465=DIRECTION('',(0.,0.,1.));
#466=VECTOR('',#465,1.);
#467=CARTESIAN_POINT('',(7.5,260.,7.5));
#468=LINE('',#467,#466);
#469=EDGE_CURVE('E210',#341,#141,#468,.T.);
#470=ORIENTED_EDGE('',*,*,#469,.F.);
#471=ORIENTED_EDGE('',*,*,#342,.T.);
#472=EDGE_LOOP('',(#463,#464,#470,#471));
#473=FACE_BOUND('',#472,.T.);
#474=ADVANCED_FACE('F261',(#473),#462,.F.);
#475=CARTESIAN_POINT('',(7.5,0.,0.));
#476=DIRECTION('',(-1.,0.,0.));
#477=DIRECTION('',(0.,0.,1.));
#478=AXIS2_PLACEMENT_3D('',#475,#476,#477);
#479=PLANE('',#478);
#480=CARTESIAN_POINT('',(7.50000000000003,0.,0.));
#481=DIRECTION('',(-1.,0.,0.));
#482=DIRECTION('',(0.,0.,1.));
#483=AXIS2_PLACEMENT_3D('',#480,#481,#482);
#484=CIRCLE('',#483,24.5);
#485=EDGE_CURVE('E201',#133,#349,#484,.T.);
#486=ORIENTED_EDGE('',*,*,#485,.T.);
#487=ORIENTED_EDGE('',*,*,#350,.T.);
#488=ORIENTED_EDGE('',*,*,#469,.T.);
#489=ORIENTED_EDGE('',*,*,#142,.T.);
#490=EDGE_LOOP('',(#486,#487,#488,#489));
#491=FACE_BOUND('',#490,.T.);
#492=ADVANCED_FACE('F476',(#491),#479,.F.);
#493=CARTESIAN_POINT('',(-7.5,0.,0.));
#494=DIRECTION('',(1.,0.,0.));
#495=DIRECTION('',(0.,0.,-1.));
#496=AXIS2_PLACEMENT_3D('',#493,#494,#495);
#497=CYLINDRICAL_SURFACE('',#496,10.);
#498=ORIENTED_EDGE('',*,*,#48,.F.);
#499=CARTESIAN_POINT('',(-4.75,0.,0.));
#500=DIRECTION('',(1.,0.,0.));
#501=DIRECTION('',(0.,1.,0.));
#502=AXIS2_PLACEMENT_3D('',#499,#500,#501);
#503=CIRCLE('',#502,10.);
#504=EDGE_CURVE('E419',#39,#239,#503,.F.);
#505=ORIENTED_EDGE('',*,*,#504,.T.);
#506=ORIENTED_EDGE('',*,*,#240,.F.);
#507=CARTESIAN_POINT('',(4.75,0.,0.));
#508=DIRECTION('',(-1.,0.,0.));
#509=DIRECTION('',(0.,-1.,0.));
#510=AXIS2_PLACEMENT_3D('',#507,#508,#509);
#511=CIRCLE('',#510,10.);
#512=EDGE_CURVE('E459',#237,#47,#511,.F.);
#513=ORIENTED_EDGE('',*,*,#512,.T.);
#514=EDGE_LOOP('',(#498,#505,#506,#513));
#515=FACE_BOUND('',#514,.T.);
#516=ADVANCED_FACE('F460',(#515),#497,.F.);
#517=CARTESIAN_POINT('',(-3.,15.,0.));
#518=DIRECTION('',(-1.,0.,0.));
#519=DIRECTION('',(0.,0.,1.));
#520=AXIS2_PLACEMENT_3D('',#517,#518,#519);
#521=PLANE('',#520);
#522=ORIENTED_EDGE('',*,*,#291,.T.);
#523=CARTESIAN_POINT('',(-3.,0.,0.));
#524=DIRECTION('',(-1.,0.,0.));
#525=DIRECTION('',(0.,0.,1.));
#526=AXIS2_PLACEMENT_3D('',#523,#524,#525);
#527=CIRCLE('',#526,15.381);
#528=EDGE_CURVE('E728',#282,#200,#527,.F.);
#529=ORIENTED_EDGE('',*,*,#528,.T.);
#530=ORIENTED_EDGE('',*,*,#201,.T.);
#531=CARTESIAN_POINT('',(-3.,0.,0.));
#532=DIRECTION('',(-1.,0.,0.));
#533=DIRECTION('',(0.,0.,1.));
#534=AXIS2_PLACEMENT_3D('',#531,#532,#533);
#535=CIRCLE('',#534,23.738);
#536=EDGE_CURVE('E226',#192,#290,#535,.T.);
#537=ORIENTED_EDGE('',*,*,#536,.T.);
#538=EDGE_LOOP('',(#522,#529,#530,#537));
#539=FACE_BOUND('',#538,.T.);
#540=ADVANCED_FACE('F493',(#539),#521,.T.);
#541=CARTESIAN_POINT('',(-8.84822894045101,0.,0.));
#542=DIRECTION('',(-1.,0.,0.));
#543=DIRECTION('',(0.,0.,1.));
#544=AXIS2_PLACEMENT_3D('',#541,#542,#543);
#545=CYLINDRICAL_SURFACE('',#544,24.5);
#546=ORIENTED_EDGE('',*,*,#326,.T.);
#547=CARTESIAN_POINT('',(-3.762,0.,0.));
#548=DIRECTION('',(-1.,0.,0.));
#549=DIRECTION('',(0.,0.,1.));
#550=AXIS2_PLACEMENT_3D('',#547,#548,#549);
#551=CIRCLE('',#550,24.5);
#552=EDGE_CURVE('E186',#317,#165,#551,.F.);
#553=ORIENTED_EDGE('',*,*,#552,.T.);
#554=ORIENTED_EDGE('',*,*,#166,.T.);
#555=ORIENTED_EDGE('',*,*,#446,.T.);
#556=EDGE_LOOP('',(#546,#553,#554,#555));
#557=FACE_BOUND('',#556,.T.);
#558=ADVANCED_FACE('F182',(#557),#545,.F.);
#559=CARTESIAN_POINT('',(-8.84822894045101,0.,0.));
#560=DIRECTION('',(-1.,0.,0.));
#561=DIRECTION('',(0.,0.,1.));
#562=AXIS2_PLACEMENT_3D('',#559,#560,#561);
#563=CYLINDRICAL_SURFACE('',#562,15.);
#564=ORIENTED_EDGE('',*,*,#256,.T.);
#565=CARTESIAN_POINT('',(-4.75,0.,0.));
#566=DIRECTION('',(1.,0.,0.));
#567=DIRECTION('',(0.,1.,0.));
#568=AXIS2_PLACEMENT_3D('',#565,#566,#567);
#569=CIRCLE('',#568,15.);
#570=EDGE_CURVE('E438',#247,#29,#569,.T.);
#571=ORIENTED_EDGE('',*,*,#570,.T.);
#572=ORIENTED_EDGE('',*,*,#32,.T.);
#573=CARTESIAN_POINT('',(-3.381,0.,0.));
#574=DIRECTION('',(-1.,0.,0.));
#575=DIRECTION('',(0.,0.,1.));
#576=AXIS2_PLACEMENT_3D('',#573,#574,#575);
#577=CIRCLE('',#576,15.);
#578=EDGE_CURVE('E283',#31,#255,#577,.T.);
#579=ORIENTED_EDGE('',*,*,#578,.T.);
#580=EDGE_LOOP('',(#564,#571,#572,#579));
#581=FACE_BOUND('',#580,.T.);
#582=ADVANCED_FACE('F496',(#581),#563,.T.);
#583=CARTESIAN_POINT('',(3.,15.,0.));
#584=DIRECTION('',(1.,0.,0.));
#585=DIRECTION('',(0.,0.,-1.));
#586=AXIS2_PLACEMENT_3D('',#583,#584,#585);
#587=PLANE('',#586);
#588=ORIENTED_EDGE('',*,*,#99,.T.);
#589=CARTESIAN_POINT('',(3.,0.,0.));
#590=DIRECTION('',(1.,0.,0.));
#591=DIRECTION('',(0.,0.,-1.));
#592=AXIS2_PLACEMENT_3D('',#589,#590,#591);
#593=CIRCLE('',#592,15.381);
#594=EDGE_CURVE('E762',#90,#392,#593,.F.);
#595=ORIENTED_EDGE('',*,*,#594,.T.);
#596=ORIENTED_EDGE('',*,*,#393,.T.);
#597=CARTESIAN_POINT('',(3.,0.,0.));
#598=DIRECTION('',(1.,0.,0.));
#599=DIRECTION('',(0.,0.,-1.));
#600=AXIS2_PLACEMENT_3D('',#597,#598,#599);
#601=CIRCLE('',#600,23.738);
#602=EDGE_CURVE('E233',#384,#98,#601,.T.);
#603=ORIENTED_EDGE('',*,*,#602,.T.);
#604=EDGE_LOOP('',(#588,#595,#596,#603));
#605=FACE_BOUND('',#604,.T.);
#606=ADVANCED_FACE('F499',(#605),#587,.T.);
#607=CARTESIAN_POINT('',(-8.84822894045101,0.,0.));
#608=DIRECTION('',(-1.,0.,0.));
#609=DIRECTION('',(0.,0.,1.));
#610=AXIS2_PLACEMENT_3D('',#607,#608,#609);
#611=CYLINDRICAL_SURFACE('',#610,15.);
#612=ORIENTED_EDGE('',*,*,#64,.T.);
#613=CARTESIAN_POINT('',(4.75,0.,0.));
#614=DIRECTION('',(-1.,0.,0.));
#615=DIRECTION('',(0.,-1.,0.));
#616=AXIS2_PLACEMENT_3D('',#613,#614,#615);
#617=CIRCLE('',#616,15.);
#618=EDGE_CURVE('E11',#55,#423,#617,.T.);
#619=ORIENTED_EDGE('',*,*,#618,.T.);
#620=ORIENTED_EDGE('',*,*,#424,.T.);
#621=CARTESIAN_POINT('',(3.381,0.,0.));
#622=DIRECTION('',(1.,0.,0.));
#623=DIRECTION('',(0.,0.,-1.));
#624=AXIS2_PLACEMENT_3D('',#621,#622,#623);
#625=CIRCLE('',#624,15.);
#626=EDGE_CURVE('E757',#415,#63,#625,.T.);
#627=ORIENTED_EDGE('',*,*,#626,.T.);
#628=EDGE_LOOP('',(#612,#619,#620,#627));
#629=FACE_BOUND('',#628,.T.);
#630=ADVANCED_FACE('F504',(#629),#611,.T.);
#631=CARTESIAN_POINT('',(-8.84822894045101,0.,0.));
#632=DIRECTION('',(-1.,0.,0.));
#633=DIRECTION('',(0.,0.,1.));
#634=AXIS2_PLACEMENT_3D('',#631,#632,#633);
#635=CYLINDRICAL_SURFACE('',#634,24.5);
#636=ORIENTED_EDGE('',*,*,#134,.T.);
#637=CARTESIAN_POINT('',(3.762,0.,0.));
#638=DIRECTION('',(1.,0.,0.));
#639=DIRECTION('',(0.,0.,-1.));
#640=AXIS2_PLACEMENT_3D('',#637,#638,#639);
#641=CIRCLE('',#640,24.5);
#642=EDGE_CURVE('E230',#125,#357,#641,.F.);
#643=ORIENTED_EDGE('',*,*,#642,.T.);
#644=ORIENTED_EDGE('',*,*,#358,.T.);
#645=ORIENTED_EDGE('',*,*,#485,.F.);
#646=EDGE_LOOP('',(#636,#643,#644,#645));
#647=FACE_BOUND('',#646,.T.);
#648=ADVANCED_FACE('F507',(#647),#635,.F.);
#649=CARTESIAN_POINT('',(5.,15.,-7.50000000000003));
#650=DIRECTION('',(-1.,0.,0.));
#651=DIRECTION('',(0.,-1.,0.));
#652=AXIS2_PLACEMENT_3D('',#649,#650,#651);
#653=PLANE('',#652);
#654=DIRECTION('',(0.,-1.,0.));
#655=VECTOR('',#654,1.);
#656=CARTESIAN_POINT('',(5.,15.,7.24999999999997));
#657=LINE('',#656,#655);
#658=CARTESIAN_POINT('',(5.,12.8452325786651,7.24999999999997));
#659=VERTEX_POINT('',#658);
#660=CARTESIAN_POINT('',(5.,7.24568837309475,7.24999999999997));
#661=VERTEX_POINT('',#660);
#662=EDGE_CURVE('E59',#659,#661,#657,.T.);
#663=ORIENTED_EDGE('',*,*,#662,.T.);
#664=CARTESIAN_POINT('',(5.,0.,0.));
#665=DIRECTION('',(-1.,0.,0.));
#666=DIRECTION('',(0.,-1.,0.));
#667=AXIS2_PLACEMENT_3D('',#664,#665,#666);
#668=CIRCLE('',#667,10.25);
#669=CARTESIAN_POINT('',(5.,7.24568837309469,-7.25000000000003));
#670=VERTEX_POINT('',#669);
#671=EDGE_CURVE('E51',#661,#670,#668,.T.);
#672=ORIENTED_EDGE('',*,*,#671,.T.);
#673=DIRECTION('',(0.,-1.,0.));
#674=VECTOR('',#673,1.);
#675=CARTESIAN_POINT('',(5.,15.,-7.25000000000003));
#676=LINE('',#675,#674);
#677=CARTESIAN_POINT('',(5.,12.8452325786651,-7.25000000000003));
#678=VERTEX_POINT('',#677);
#679=EDGE_CURVE('E406',#670,#678,#676,.F.);
#680=ORIENTED_EDGE('',*,*,#679,.T.);
#681=CARTESIAN_POINT('',(5.,0.,0.));
#682=DIRECTION('',(-1.,0.,0.));
#683=DIRECTION('',(0.,-1.,0.));
#684=AXIS2_PLACEMENT_3D('',#681,#682,#683);
#685=CIRCLE('',#684,14.75);
#686=EDGE_CURVE('E64',#678,#659,#685,.F.);
#687=ORIENTED_EDGE('',*,*,#686,.T.);
#688=EDGE_LOOP('',(#663,#672,#680,#687));
#689=FACE_BOUND('',#688,.T.);
#690=ADVANCED_FACE('F447',(#689),#653,.F.);
#691=CARTESIAN_POINT('',(-5.,15.,-7.50000000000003));
#692=DIRECTION('',(1.,0.,0.));
#693=DIRECTION('',(0.,1.,0.));
#694=AXIS2_PLACEMENT_3D('',#691,#692,#693);
#695=PLANE('',#694);
#696=DIRECTION('',(0.,1.,0.));
#697=VECTOR('',#696,1.);
#698=CARTESIAN_POINT('',(-5.,15.,-7.25000000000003));
#699=LINE('',#698,#697);
#700=CARTESIAN_POINT('',(-5.,12.8452325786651,-7.25000000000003));
#701=VERTEX_POINT('',#700);
#702=CARTESIAN_POINT('',(-5.,7.24568837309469,-7.25000000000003));
#703=VERTEX_POINT('',#702);
#704=EDGE_CURVE('E430',#701,#703,#699,.F.);
#705=ORIENTED_EDGE('',*,*,#704,.T.);
#706=CARTESIAN_POINT('',(-5.,0.,0.));
#707=DIRECTION('',(1.,0.,0.));
#708=DIRECTION('',(0.,1.,0.));
#709=AXIS2_PLACEMENT_3D('',#706,#707,#708);
#710=CIRCLE('',#709,10.25);
#711=CARTESIAN_POINT('',(-5.,7.24568837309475,7.24999999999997));
#712=VERTEX_POINT('',#711);
#713=EDGE_CURVE('E417',#703,#712,#710,.T.);
#714=ORIENTED_EDGE('',*,*,#713,.T.);
#715=DIRECTION('',(0.,1.,0.));
#716=VECTOR('',#715,1.);
#717=CARTESIAN_POINT('',(-5.,15.,7.24999999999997));
#718=LINE('',#717,#716);
#719=CARTESIAN_POINT('',(-5.,12.8452325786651,7.24999999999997));
#720=VERTEX_POINT('',#719);
#721=EDGE_CURVE('E423',#712,#720,#718,.T.);
#722=ORIENTED_EDGE('',*,*,#721,.T.);
#723=CARTESIAN_POINT('',(-5.,0.,0.));
#724=DIRECTION('',(1.,0.,0.));
#725=DIRECTION('',(0.,1.,0.));
#726=AXIS2_PLACEMENT_3D('',#723,#724,#725);
#727=CIRCLE('',#726,14.75);
#728=EDGE_CURVE('E427',#720,#701,#727,.F.);
#729=ORIENTED_EDGE('',*,*,#728,.T.);
#730=EDGE_LOOP('',(#705,#714,#722,#729));
#731=FACE_BOUND('',#730,.T.);
#732=ADVANCED_FACE('F259',(#731),#695,.F.);
#733=CARTESIAN_POINT('',(-3.762,0.,0.));
#734=DIRECTION('',(-1.,0.,0.));
#735=DIRECTION('',(0.,0.,1.));
#736=AXIS2_PLACEMENT_3D('',#733,#734,#735);
#737=TOROIDAL_SURFACE('',#736,23.738,0.762);
#738=ORIENTED_EDGE('',*,*,#193,.F.);
#739=ORIENTED_EDGE('',*,*,#552,.F.);
#740=ORIENTED_EDGE('',*,*,#318,.F.);
#741=ORIENTED_EDGE('',*,*,#536,.F.);
#742=EDGE_LOOP('',(#738,#739,#740,#741));
#743=FACE_BOUND('',#742,.T.);
#744=ADVANCED_FACE('F253',(#743),#737,.F.);
#745=CARTESIAN_POINT('',(3.762,0.,0.));
#746=DIRECTION('',(1.,0.,0.));
#747=DIRECTION('',(0.,0.,-1.));
#748=AXIS2_PLACEMENT_3D('',#745,#746,#747);
#749=TOROIDAL_SURFACE('',#748,23.738,0.762);
#750=ORIENTED_EDGE('',*,*,#126,.F.);
#751=ORIENTED_EDGE('',*,*,#602,.F.);
#752=ORIENTED_EDGE('',*,*,#385,.F.);
#753=ORIENTED_EDGE('',*,*,#642,.F.);
#754=EDGE_LOOP('',(#750,#751,#752,#753));
#755=FACE_BOUND('',#754,.T.);
#756=ADVANCED_FACE('F258',(#755),#749,.F.);
#757=CARTESIAN_POINT('',(-3.381,0.,0.));
#758=DIRECTION('',(-1.,0.,0.));
#759=DIRECTION('',(0.,0.,1.));
#760=AXIS2_PLACEMENT_3D('',#757,#758,#759);
#761=TOROIDAL_SURFACE('',#760,15.381,0.381);
#762=ORIENTED_EDGE('',*,*,#222,.F.);
#763=ORIENTED_EDGE('',*,*,#528,.F.);
#764=ORIENTED_EDGE('',*,*,#283,.F.);
#765=ORIENTED_EDGE('',*,*,#578,.F.);
#766=EDGE_LOOP('',(#762,#763,#764,#765));
#767=FACE_BOUND('',#766,.T.);
#768=ADVANCED_FACE('F266',(#767),#761,.F.);
#769=CARTESIAN_POINT('',(3.381,0.,0.));
#770=DIRECTION('',(1.,0.,0.));
#771=DIRECTION('',(0.,0.,-1.));
#772=AXIS2_PLACEMENT_3D('',#769,#770,#771);
#773=TOROIDAL_SURFACE('',#772,15.381,0.381);
#774=ORIENTED_EDGE('',*,*,#91,.F.);
#775=ORIENTED_EDGE('',*,*,#626,.F.);
#776=ORIENTED_EDGE('',*,*,#416,.F.);
#777=ORIENTED_EDGE('',*,*,#594,.F.);
#778=EDGE_LOOP('',(#774,#775,#776,#777));
#779=FACE_BOUND('',#778,.T.);
#780=ADVANCED_FACE('F318',(#779),#773,.F.);
#781=CARTESIAN_POINT('',(-4.75,0.,0.));
#782=DIRECTION('',(1.,0.,0.));
#783=DIRECTION('',(0.,1.,0.));
#784=AXIS2_PLACEMENT_3D('',#781,#782,#783);
#785=TOROIDAL_SURFACE('',#784,14.75,0.25);
#786=CARTESIAN_POINT('',(-4.75,12.9903810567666,-7.50000000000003));
#787=CARTESIAN_POINT('',(-4.76271945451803,12.9903904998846,-7.50001659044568));
#788=CARTESIAN_POINT('',(-4.77542458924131,12.9898213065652,-7.49903048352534));
#789=CARTESIAN_POINT('',(-4.80039774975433,12.9876020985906,-7.49518707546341));
#790=CARTESIAN_POINT('',(-4.81266741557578,12.9859567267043,-7.49233781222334));
#791=CARTESIAN_POINT('',(-4.83646615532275,12.9816622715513,-7.48490340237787));
#792=CARTESIAN_POINT('',(-4.84799584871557,12.9790140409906,-7.48031973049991));
#793=CARTESIAN_POINT('',(-4.87006947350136,12.9728307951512,-7.46962194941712));
#794=CARTESIAN_POINT('',(-4.88061259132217,12.9692950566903,-7.46350659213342));
#795=CARTESIAN_POINT('',(-4.90102325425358,12.9612678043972,-7.44962974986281));
#796=CARTESIAN_POINT('',(-4.91082851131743,12.9567366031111,-7.44179997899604));
#797=CARTESIAN_POINT('',(-4.92898839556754,12.9469942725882,-7.42497579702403));
#798=CARTESIAN_POINT('',(-4.93734263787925,12.9417829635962,-7.41598107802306));
#799=CARTESIAN_POINT('',(-4.95348698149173,12.930126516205,-7.39587557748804));
#800=CARTESIAN_POINT('',(-4.96107044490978,12.9236087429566,-7.38464114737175));
#801=CARTESIAN_POINT('',(-4.97424438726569,12.910072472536,-7.36132835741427));
#802=CARTESIAN_POINT('',(-4.97983287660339,12.9030534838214,-7.34924916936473));
#803=CARTESIAN_POINT('',(-4.98944198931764,12.8879780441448,-7.32332772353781));
#804=CARTESIAN_POINT('',(-4.99325505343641,12.8798873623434,-7.30942874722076));
#805=CARTESIAN_POINT('',(-4.99843991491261,12.8635114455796,-7.2813239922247));
#806=CARTESIAN_POINT('',(-4.99981661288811,12.8552266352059,-7.26711888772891));
#807=CARTESIAN_POINT('',(-4.99999429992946,12.8463715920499,-7.25195084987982));
#808=CARTESIAN_POINT('',(-5.00000000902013,12.8458020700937,-7.25097536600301));
#809=CARTESIAN_POINT('',(-5.,12.8452325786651,-7.25000000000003));
#810=B_SPLINE_CURVE_WITH_KNOTS('',3,(#786,#787,#788,#789,#790,#791,#792,#793,#794,#795,#796,
#797,#798,#799,#800,#801,#802,#803,#804,#805,#806,#807,#808,#809),.UNSPECIFIED.,.F.,.F.,(4,2,2,
2,2,2,2,2,2,2,2,4),(0.,0.0380850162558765,0.076006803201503,0.113896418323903,0.151817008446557,
0.191680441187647,0.231554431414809,0.276496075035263,0.321482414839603,0.370881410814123,
0.420180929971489,0.423569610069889),.UNSPECIFIED.);
#811=EDGE_CURVE('E343',#701,#247,#810,.F.);
#812=ORIENTED_EDGE('',*,*,#811,.F.);
#813=ORIENTED_EDGE('',*,*,#728,.F.);
#814=CARTESIAN_POINT('',(-4.75,12.9903810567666,7.49999999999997));
#815=CARTESIAN_POINT('',(-4.76271945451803,12.9903904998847,7.50001659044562));
#816=CARTESIAN_POINT('',(-4.77542458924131,12.9898213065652,7.49903048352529));
#817=CARTESIAN_POINT('',(-4.80039774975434,12.9876020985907,7.49518707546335));
#818=CARTESIAN_POINT('',(-4.81266741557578,12.9859567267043,7.49233781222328));
#819=CARTESIAN_POINT('',(-4.83646615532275,12.9816622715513,7.48490340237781));
#820=CARTESIAN_POINT('',(-4.84799584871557,12.9790140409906,7.48031973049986));
#821=CARTESIAN_POINT('',(-4.87006947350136,12.9728307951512,7.46962194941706));
#822=CARTESIAN_POINT('',(-4.88061259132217,12.9692950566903,7.46350659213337));
#823=CARTESIAN_POINT('',(-4.90102325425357,12.9612678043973,7.44962974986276));
#824=CARTESIAN_POINT('',(-4.91082851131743,12.9567366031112,7.44179997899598));
#825=CARTESIAN_POINT('',(-4.92898839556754,12.9469942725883,7.42497579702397));
#826=CARTESIAN_POINT('',(-4.93734263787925,12.9417829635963,7.41598107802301));
#827=CARTESIAN_POINT('',(-4.95348698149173,12.930126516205,7.39587557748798));
#828=CARTESIAN_POINT('',(-4.96107044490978,12.9236087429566,7.38464114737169));
#829=CARTESIAN_POINT('',(-4.97424438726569,12.910072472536,7.36132835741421));
#830=CARTESIAN_POINT('',(-4.97983287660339,12.9030534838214,7.34924916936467));
#831=CARTESIAN_POINT('',(-4.98944198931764,12.8879780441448,7.32332772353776));
#832=CARTESIAN_POINT('',(-4.99325505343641,12.8798873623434,7.30942874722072));
#833=CARTESIAN_POINT('',(-4.99843991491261,12.8635114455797,7.28132399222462));
#834=CARTESIAN_POINT('',(-4.99981661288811,12.8552266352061,7.26711888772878));
#835=CARTESIAN_POINT('',(-4.99999429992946,12.8463715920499,7.25195084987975));
#836=CARTESIAN_POINT('',(-5.00000000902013,12.8458020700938,7.25097536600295));
#837=CARTESIAN_POINT('',(-5.,12.8452325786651,7.24999999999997));
#838=B_SPLINE_CURVE_WITH_KNOTS('',3,(#814,#815,#816,#817,#818,#819,#820,#821,#822,#823,#824,
#825,#826,#827,#828,#829,#830,#831,#832,#833,#834,#835,#836,#837),.UNSPECIFIED.,.F.,.F.,(4,2,2,
2,2,2,2,2,2,2,2,4),(0.,0.0380850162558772,0.0760068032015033,0.113896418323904,
0.151817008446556,0.191680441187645,0.231554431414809,0.276496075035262,0.321482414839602,
0.370881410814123,0.420180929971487,0.423569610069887),.UNSPECIFIED.);
#839=EDGE_CURVE('E202',#29,#720,#838,.T.);
#840=ORIENTED_EDGE('',*,*,#839,.F.);
#841=ORIENTED_EDGE('',*,*,#570,.F.);
#842=EDGE_LOOP('',(#812,#813,#840,#841));
#843=FACE_BOUND('',#842,.T.);
#844=ADVANCED_FACE('F322',(#843),#785,.T.);
#845=CARTESIAN_POINT('',(-4.75,15.,7.24999999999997));
#846=DIRECTION('',(0.,1.,0.));
#847=DIRECTION('',(0.,0.,1.));
#848=AXIS2_PLACEMENT_3D('',#845,#846,#847);
#849=CYLINDRICAL_SURFACE('',#848,0.25);
#850=ORIENTED_EDGE('',*,*,#839,.T.);
#851=ORIENTED_EDGE('',*,*,#721,.F.);
#852=CARTESIAN_POINT('',(-4.75,6.61437827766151,7.49999999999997));
#853=CARTESIAN_POINT('',(-4.75567065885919,6.61436201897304,7.50000607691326));
#854=CARTESIAN_POINT('',(-4.76131702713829,6.6148879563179,7.49980736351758));
#855=CARTESIAN_POINT('',(-4.77234473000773,6.61686952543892,7.49905826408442));
#856=CARTESIAN_POINT('',(-4.77772861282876,6.61831251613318,7.49851265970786));
#857=CARTESIAN_POINT('',(-4.78950980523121,6.62244930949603,7.496947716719));
#858=CARTESIAN_POINT('',(-4.79581466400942,6.62536847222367,7.4958429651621));
#859=CARTESIAN_POINT('',(-4.80787010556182,6.63211266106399,7.49328837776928));
#860=CARTESIAN_POINT('',(-4.81361730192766,6.63594278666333,7.49183659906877));
#861=CARTESIAN_POINT('',(-4.8284151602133,6.64715267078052,7.48758315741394));
#862=CARTESIAN_POINT('',(-4.83693895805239,6.65513151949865,7.48455129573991));
#863=CARTESIAN_POINT('',(-4.85270254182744,6.67210281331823,7.47808906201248));
#864=CARTESIAN_POINT('',(-4.85993950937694,6.68109741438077,7.47465784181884));
#865=CARTESIAN_POINT('',(-4.87587564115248,6.7030914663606,7.46624928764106));
#866=CARTESIAN_POINT('',(-4.88414705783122,6.71635618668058,7.46116407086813));
#867=CARTESIAN_POINT('',(-4.89933297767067,6.743544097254,7.45070856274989));
#868=CARTESIAN_POINT('',(-4.90624477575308,6.75746853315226,7.44533772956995));
#869=CARTESIAN_POINT('',(-4.92545351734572,6.79995897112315,7.42889595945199));
#870=CARTESIAN_POINT('',(-4.93615332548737,6.82913157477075,7.41753794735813));
#871=CARTESIAN_POINT('',(-4.95513725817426,6.8898611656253,7.39373693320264));
#872=CARTESIAN_POINT('',(-4.96324824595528,6.92145910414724,7.3812690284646));
#873=CARTESIAN_POINT('',(-4.97688018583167,6.98510727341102,7.35597970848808));
#874=CARTESIAN_POINT('',(-4.98239809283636,7.01715799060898,7.34315789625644));
#875=CARTESIAN_POINT('',(-4.9911561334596,7.08135331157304,7.31729894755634));
#876=CARTESIAN_POINT('',(-4.99440347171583,7.11349729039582,7.30426262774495));
#877=CARTESIAN_POINT('',(-4.99878493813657,7.1778443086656,7.27798816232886));
#878=CARTESIAN_POINT('',(-4.99991944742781,7.21004733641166,7.2647500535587));
#879=CARTESIAN_POINT('',(-4.99999861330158,7.24337162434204,7.25095911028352));
#880=CARTESIAN_POINT('',(-4.9999999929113,7.24453002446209,7.25047960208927));
#881=CARTESIAN_POINT('',(-5.,7.24568837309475,7.24999999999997));
#882=B_SPLINE_CURVE_WITH_KNOTS('',3,(#852,#853,#854,#855,#856,#857,#858,#859,#860,#861,#862,
#863,#864,#865,#866,#867,#868,#869,#870,#871,#872,#873,#874,#875,#876,#877,#878,#879,#880,#881),
.UNSPECIFIED.,.F.,.F.,(4,2,2,2,2,2,2,2,2,2,2,2,2,2,4),(0.,0.0169451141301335,0.0336615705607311,
0.0546483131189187,0.0757554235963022,0.111739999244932,0.147802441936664,0.197002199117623,
0.246298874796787,0.345301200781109,0.449965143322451,0.554751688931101,0.659204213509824,
0.763637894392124,0.76739905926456),.UNSPECIFIED.);
#883=EDGE_CURVE('E351',#39,#712,#882,.T.);
#884=ORIENTED_EDGE('',*,*,#883,.F.);
#885=ORIENTED_EDGE('',*,*,#40,.F.);
#886=EDGE_LOOP('',(#850,#851,#884,#885));
#887=FACE_BOUND('',#886,.T.);
#888=ADVANCED_FACE('F330',(#887),#849,.T.);
#889=CARTESIAN_POINT('',(-4.75000000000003,260.,-7.25));
#890=DIRECTION('',(0.,1.,0.));
#891=DIRECTION('',(0.,0.,1.));
#892=AXIS2_PLACEMENT_3D('',#889,#890,#891);
#893=CYLINDRICAL_SURFACE('',#892,0.25);
#894=ORIENTED_EDGE('',*,*,#811,.T.);
#895=ORIENTED_EDGE('',*,*,#248,.F.);
#896=CARTESIAN_POINT('',(-4.75,6.61437827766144,-7.50000000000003));
#897=CARTESIAN_POINT('',(-4.75567065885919,6.61436201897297,-7.50000607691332));
#898=CARTESIAN_POINT('',(-4.76131702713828,6.61488795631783,-7.49980736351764));
#899=CARTESIAN_POINT('',(-4.77234473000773,6.61686952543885,-7.49905826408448));
#900=CARTESIAN_POINT('',(-4.77772861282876,6.61831251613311,-7.49851265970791));
#901=CARTESIAN_POINT('',(-4.78950980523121,6.62244930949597,-7.49694771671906));
#902=CARTESIAN_POINT('',(-4.79581466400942,6.6253684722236,-7.49584296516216));
#903=CARTESIAN_POINT('',(-4.80787010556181,6.63211266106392,-7.49328837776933));
#904=CARTESIAN_POINT('',(-4.81361730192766,6.63594278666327,-7.49183659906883));
#905=CARTESIAN_POINT('',(-4.8284151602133,6.64715267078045,-7.487583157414));
#906=CARTESIAN_POINT('',(-4.83693895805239,6.65513151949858,-7.48455129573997));
#907=CARTESIAN_POINT('',(-4.85270254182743,6.67210281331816,-7.47808906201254));
#908=CARTESIAN_POINT('',(-4.85993950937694,6.6810974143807,-7.4746578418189));
#909=CARTESIAN_POINT('',(-4.87587564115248,6.70309146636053,-7.46624928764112));
#910=CARTESIAN_POINT('',(-4.88414705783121,6.71635618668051,-7.46116407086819));
#911=CARTESIAN_POINT('',(-4.89933297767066,6.74354409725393,-7.45070856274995));
#912=CARTESIAN_POINT('',(-4.90624477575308,6.75746853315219,-7.44533772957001));
#913=CARTESIAN_POINT('',(-4.92545351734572,6.79995897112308,-7.42889595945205));
#914=CARTESIAN_POINT('',(-4.93615332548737,6.82913157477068,-7.41753794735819));
#915=CARTESIAN_POINT('',(-4.95513725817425,6.88986116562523,-7.3937369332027));
#916=CARTESIAN_POINT('',(-4.96324824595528,6.92145910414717,-7.38126902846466));
#917=CARTESIAN_POINT('',(-4.97688018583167,6.98510727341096,-7.35597970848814));
#918=CARTESIAN_POINT('',(-4.98239809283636,7.01715799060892,-7.34315789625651));
#919=CARTESIAN_POINT('',(-4.9911561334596,7.08135331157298,-7.3172989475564));
#920=CARTESIAN_POINT('',(-4.99440347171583,7.11349729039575,-7.304262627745));
#921=CARTESIAN_POINT('',(-4.99878493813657,7.17784430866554,-7.27798816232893));
#922=CARTESIAN_POINT('',(-4.99991944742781,7.21004733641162,-7.26475005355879));
#923=CARTESIAN_POINT('',(-4.99999861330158,7.24337162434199,-7.25095911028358));
#924=CARTESIAN_POINT('',(-4.9999999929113,7.24453002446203,-7.25047960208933));
#925=CARTESIAN_POINT('',(-5.,7.24568837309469,-7.25000000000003));
#926=B_SPLINE_CURVE_WITH_KNOTS('',3,(#896,#897,#898,#899,#900,#901,#902,#903,#904,#905,#906,
#907,#908,#909,#910,#911,#912,#913,#914,#915,#916,#917,#918,#919,#920,#921,#922,#923,#924,#925),
.UNSPECIFIED.,.F.,.F.,(4,2,2,2,2,2,2,2,2,2,2,2,2,2,4),(0.,0.0169451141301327,0.0336615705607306,
0.0546483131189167,0.0757554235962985,0.11173999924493,0.147802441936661,0.197002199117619,
0.246298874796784,0.345301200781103,0.449965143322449,0.554751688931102,0.659204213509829,
0.763637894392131,0.767399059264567),.UNSPECIFIED.);
#927=EDGE_CURVE('E336',#703,#239,#926,.F.);
#928=ORIENTED_EDGE('',*,*,#927,.F.);
#929=ORIENTED_EDGE('',*,*,#704,.F.);
#930=EDGE_LOOP('',(#894,#895,#928,#929));
#931=FACE_BOUND('',#930,.T.);
#932=ADVANCED_FACE('F324',(#931),#893,.T.);
#933=CARTESIAN_POINT('',(-4.75,0.,0.));
#934=DIRECTION('',(1.,0.,0.));
#935=DIRECTION('',(0.,1.,0.));
#936=AXIS2_PLACEMENT_3D('',#933,#934,#935);
#937=TOROIDAL_SURFACE('',#936,10.25,0.25);
#938=ORIENTED_EDGE('',*,*,#883,.T.);
#939=ORIENTED_EDGE('',*,*,#713,.F.);
#940=ORIENTED_EDGE('',*,*,#927,.T.);
#941=ORIENTED_EDGE('',*,*,#504,.F.);
#942=EDGE_LOOP('',(#938,#939,#940,#941));
#943=FACE_BOUND('',#942,.T.);
#944=ADVANCED_FACE('F329',(#943),#937,.T.);
#945=CARTESIAN_POINT('',(4.75,0.,0.));
#946=DIRECTION('',(-1.,0.,0.));
#947=DIRECTION('',(0.,-1.,0.));
#948=AXIS2_PLACEMENT_3D('',#945,#946,#947);
#949=TOROIDAL_SURFACE('',#948,14.75,0.25);
#950=CARTESIAN_POINT('',(4.75,12.9903810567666,7.49999999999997));
#951=CARTESIAN_POINT('',(4.76271945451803,12.9903904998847,7.50001659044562));
#952=CARTESIAN_POINT('',(4.77542458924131,12.9898213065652,7.49903048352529));
#953=CARTESIAN_POINT('',(4.80039774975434,12.9876020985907,7.49518707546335));
#954=CARTESIAN_POINT('',(4.81266741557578,12.9859567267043,7.49233781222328));
#955=CARTESIAN_POINT('',(4.83646615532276,12.9816622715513,7.48490340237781));
#956=CARTESIAN_POINT('',(4.84799584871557,12.9790140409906,7.48031973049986));
#957=CARTESIAN_POINT('',(4.87006947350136,12.9728307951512,7.46962194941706));
#958=CARTESIAN_POINT('',(4.88061259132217,12.9692950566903,7.46350659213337));
#959=CARTESIAN_POINT('',(4.90102325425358,12.9612678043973,7.44962974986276));
#960=CARTESIAN_POINT('',(4.91082851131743,12.9567366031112,7.44179997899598));
#961=CARTESIAN_POINT('',(4.92898839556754,12.9469942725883,7.42497579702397));
#962=CARTESIAN_POINT('',(4.93734263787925,12.9417829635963,7.41598107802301));
#963=CARTESIAN_POINT('',(4.95348698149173,12.930126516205,7.39587557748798));
#964=CARTESIAN_POINT('',(4.96107044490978,12.9236087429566,7.38464114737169));
#965=CARTESIAN_POINT('',(4.97424438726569,12.910072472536,7.3613283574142));
#966=CARTESIAN_POINT('',(4.97983287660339,12.9030534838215,7.34924916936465));
#967=CARTESIAN_POINT('',(4.98944198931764,12.8879780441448,7.32332772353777));
#968=CARTESIAN_POINT('',(4.99325505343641,12.8798873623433,7.30942874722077));
#969=CARTESIAN_POINT('',(4.99843991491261,12.8635114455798,7.28132399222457));
#970=CARTESIAN_POINT('',(4.99981661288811,12.8552266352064,7.26711888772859));
#971=CARTESIAN_POINT('',(4.99999429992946,12.8463715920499,7.25195084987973));
#972=CARTESIAN_POINT('',(5.00000000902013,12.8458020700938,7.25097536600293));
#973=CARTESIAN_POINT('',(5.,12.8452325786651,7.24999999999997));
#974=B_SPLINE_CURVE_WITH_KNOTS('',3,(#950,#951,#952,#953,#954,#955,#956,#957,#958,#959,#960,
#961,#962,#963,#964,#965,#966,#967,#968,#969,#970,#971,#972,#973),.UNSPECIFIED.,.F.,.F.,(4,2,2,
2,2,2,2,2,2,2,2,4),(0.,0.0380850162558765,0.0760068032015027,0.113896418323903,
0.151817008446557,0.191680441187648,0.231554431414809,0.276496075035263,0.321482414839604,
0.37088141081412,0.420180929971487,0.423569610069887),.UNSPECIFIED.);
#975=EDGE_CURVE('E382',#659,#55,#974,.F.);
#976=ORIENTED_EDGE('',*,*,#975,.F.);
#977=ORIENTED_EDGE('',*,*,#686,.F.);
#978=CARTESIAN_POINT('',(4.75,12.9903810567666,-7.50000000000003));
#979=CARTESIAN_POINT('',(4.76271945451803,12.9903904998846,-7.50001659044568));
#980=CARTESIAN_POINT('',(4.77542458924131,12.9898213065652,-7.49903048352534));
#981=CARTESIAN_POINT('',(4.80039774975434,12.9876020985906,-7.49518707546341));
#982=CARTESIAN_POINT('',(4.81266741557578,12.9859567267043,-7.49233781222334));
#983=CARTESIAN_POINT('',(4.83646615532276,12.9816622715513,-7.48490340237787));
#984=CARTESIAN_POINT('',(4.84799584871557,12.9790140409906,-7.48031973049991));
#985=CARTESIAN_POINT('',(4.87006947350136,12.9728307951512,-7.46962194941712));
#986=CARTESIAN_POINT('',(4.88061259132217,12.9692950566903,-7.46350659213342));
#987=CARTESIAN_POINT('',(4.90102325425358,12.9612678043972,-7.44962974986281));
#988=CARTESIAN_POINT('',(4.91082851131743,12.9567366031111,-7.44179997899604));
#989=CARTESIAN_POINT('',(4.92898839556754,12.9469942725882,-7.42497579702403));
#990=CARTESIAN_POINT('',(4.93734263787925,12.9417829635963,-7.41598107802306));
#991=CARTESIAN_POINT('',(4.95348698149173,12.930126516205,-7.39587557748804));
#992=CARTESIAN_POINT('',(4.96107044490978,12.9236087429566,-7.38464114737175));
#993=CARTESIAN_POINT('',(4.97424438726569,12.910072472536,-7.36132835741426));
#994=CARTESIAN_POINT('',(4.97983287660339,12.9030534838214,-7.3492491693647));
#995=CARTESIAN_POINT('',(4.98944198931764,12.8879780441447,-7.32332772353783));
#996=CARTESIAN_POINT('',(4.99325505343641,12.8798873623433,-7.30942874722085));
#997=CARTESIAN_POINT('',(4.99843991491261,12.8635114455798,-7.28132399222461));
#998=CARTESIAN_POINT('',(4.99981661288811,12.8552266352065,-7.26711888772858));
#999=CARTESIAN_POINT('',(4.99999429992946,12.8463715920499,-7.25195084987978));
#1000=CARTESIAN_POINT('',(5.00000000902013,12.8458020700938,-7.25097536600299));
#1001=CARTESIAN_POINT('',(5.,12.8452325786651,-7.25000000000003));
#1002=B_SPLINE_CURVE_WITH_KNOTS('',3,(#978,#979,#980,#981,#982,#983,#984,#985,#986,#987,#988,
#989,#990,#991,#992,#993,#994,#995,#996,#997,#998,#999,#1000,#1001),.UNSPECIFIED.,.F.,.F.,(4,2,
2,2,2,2,2,2,2,2,2,4),(0.,0.0380850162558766,0.0760068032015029,0.113896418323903,
0.151817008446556,0.191680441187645,0.231554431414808,0.276496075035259,0.321482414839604,
0.37088141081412,0.420180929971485,0.423569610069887),.UNSPECIFIED.);
#1003=EDGE_CURVE('E42',#423,#678,#1002,.T.);
#1004=ORIENTED_EDGE('',*,*,#1003,.F.);
#1005=ORIENTED_EDGE('',*,*,#618,.F.);
#1006=EDGE_LOOP('',(#976,#977,#1004,#1005));
#1007=FACE_BOUND('',#1006,.T.);
#1008=ADVANCED_FACE('F39',(#1007),#949,.T.);
#1009=CARTESIAN_POINT('',(4.74999999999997,260.,-7.25));
#1010=DIRECTION('',(0.,-1.,0.));
#1011=DIRECTION('',(0.,0.,-1.));
#1012=AXIS2_PLACEMENT_3D('',#1009,#1010,#1011);
#1013=CYLINDRICAL_SURFACE('',#1012,0.25);
#1014=ORIENTED_EDGE('',*,*,#1003,.T.);
#1015=ORIENTED_EDGE('',*,*,#679,.F.);
#1016=CARTESIAN_POINT('',(4.75,6.61437827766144,-7.50000000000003));
#1017=CARTESIAN_POINT('',(4.75567065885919,6.61436201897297,-7.50000607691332));
#1018=CARTESIAN_POINT('',(4.76131702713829,6.61488795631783,-7.49980736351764));
#1019=CARTESIAN_POINT('',(4.77234473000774,6.61686952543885,-7.49905826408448));
#1020=CARTESIAN_POINT('',(4.77772861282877,6.61831251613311,-7.49851265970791));
#1021=CARTESIAN_POINT('',(4.78950980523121,6.62244930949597,-7.49694771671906));
#1022=CARTESIAN_POINT('',(4.79581466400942,6.6253684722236,-7.49584296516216));
#1023=CARTESIAN_POINT('',(4.80787010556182,6.63211266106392,-7.49328837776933));
#1024=CARTESIAN_POINT('',(4.81361730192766,6.63594278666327,-7.49183659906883));
#1025=CARTESIAN_POINT('',(4.82841516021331,6.64715267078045,-7.487583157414));
#1026=CARTESIAN_POINT('',(4.83693895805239,6.65513151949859,-7.48455129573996));
#1027=CARTESIAN_POINT('',(4.85270254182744,6.67210281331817,-7.47808906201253));
#1028=CARTESIAN_POINT('',(4.85993950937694,6.6810974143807,-7.4746578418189));
#1029=CARTESIAN_POINT('',(4.87587564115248,6.70309146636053,-7.46624928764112));
#1030=CARTESIAN_POINT('',(4.88414705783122,6.71635618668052,-7.46116407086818));
#1031=CARTESIAN_POINT('',(4.89933297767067,6.74354409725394,-7.45070856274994));
#1032=CARTESIAN_POINT('',(4.90624477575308,6.75746853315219,-7.44533772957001));
#1033=CARTESIAN_POINT('',(4.92545351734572,6.79995897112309,-7.42889595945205));
#1034=CARTESIAN_POINT('',(4.93615332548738,6.82913157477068,-7.41753794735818));
#1035=CARTESIAN_POINT('',(4.95513725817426,6.88986116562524,-7.3937369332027));
#1036=CARTESIAN_POINT('',(4.96324824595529,6.92145910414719,-7.38126902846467));
#1037=CARTESIAN_POINT('',(4.97688018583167,6.98510727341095,-7.35597970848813));
#1038=CARTESIAN_POINT('',(4.98239809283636,7.01715799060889,-7.34315789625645));
#1039=CARTESIAN_POINT('',(4.9911561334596,7.081353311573,-7.31729894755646));
#1040=CARTESIAN_POINT('',(4.99440347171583,7.11349729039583,-7.30426262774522));
#1041=CARTESIAN_POINT('',(4.99878493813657,7.17784430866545,-7.27798816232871));
#1042=CARTESIAN_POINT('',(4.99991944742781,7.21004733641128,-7.26475005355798));
#1043=CARTESIAN_POINT('',(4.99999861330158,7.24337162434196,-7.25095911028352));
#1044=CARTESIAN_POINT('',(4.9999999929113,7.24453002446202,-7.2504796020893));
#1045=CARTESIAN_POINT('',(5.,7.24568837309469,-7.25000000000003));
#1046=B_SPLINE_CURVE_WITH_KNOTS('',3,(#1016,#1017,#1018,#1019,#1020,#1021,#1022,#1023,#1024,
#1025,#1026,#1027,#1028,#1029,#1030,#1031,#1032,#1033,#1034,#1035,#1036,#1037,#1038,#1039,#1040,
#1041,#1042,#1043,#1044,#1045),.UNSPECIFIED.,.F.,.F.,(4,2,2,2,2,2,2,2,2,2,2,2,2,2,4),(0.,
0.0169451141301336,0.0336615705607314,0.0546483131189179,0.0757554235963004,0.111739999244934,
0.147802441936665,0.197002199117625,0.246298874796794,0.345301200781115,0.449965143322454,
0.554751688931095,0.659204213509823,0.763637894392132,0.767399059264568),.UNSPECIFIED.);
#1047=EDGE_CURVE('E388',#237,#670,#1046,.T.);
#1048=ORIENTED_EDGE('',*,*,#1047,.F.);
#1049=ORIENTED_EDGE('',*,*,#430,.F.);
#1050=EDGE_LOOP('',(#1014,#1015,#1048,#1049));
#1051=FACE_BOUND('',#1050,.T.);
#1052=ADVANCED_FACE('F372',(#1051),#1013,.T.);
#1053=CARTESIAN_POINT('',(4.75,15.,7.24999999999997));
#1054=DIRECTION('',(0.,-1.,0.));
#1055=DIRECTION('',(0.,0.,-1.));
#1056=AXIS2_PLACEMENT_3D('',#1053,#1054,#1055);
#1057=CYLINDRICAL_SURFACE('',#1056,0.25);
#1058=ORIENTED_EDGE('',*,*,#975,.T.);
#1059=ORIENTED_EDGE('',*,*,#56,.F.);
#1060=CARTESIAN_POINT('',(4.75,6.61437827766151,7.49999999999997));
#1061=CARTESIAN_POINT('',(4.75567065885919,6.61436201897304,7.50000607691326));
#1062=CARTESIAN_POINT('',(4.76131702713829,6.6148879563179,7.49980736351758));
#1063=CARTESIAN_POINT('',(4.77234473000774,6.61686952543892,7.49905826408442));
#1064=CARTESIAN_POINT('',(4.77772861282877,6.61831251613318,7.49851265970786));
#1065=CARTESIAN_POINT('',(4.78950980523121,6.62244930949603,7.496947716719));
#1066=CARTESIAN_POINT('',(4.79581466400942,6.62536847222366,7.4958429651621));
#1067=CARTESIAN_POINT('',(4.80787010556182,6.63211266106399,7.49328837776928));
#1068=CARTESIAN_POINT('',(4.81361730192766,6.63594278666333,7.49183659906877));
#1069=CARTESIAN_POINT('',(4.8284151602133,6.64715267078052,7.48758315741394));
#1070=CARTESIAN_POINT('',(4.83693895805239,6.65513151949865,7.48455129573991));
#1071=CARTESIAN_POINT('',(4.85270254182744,6.67210281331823,7.47808906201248));
#1072=CARTESIAN_POINT('',(4.85993950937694,6.68109741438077,7.47465784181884));
#1073=CARTESIAN_POINT('',(4.87587564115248,6.7030914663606,7.46624928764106));
#1074=CARTESIAN_POINT('',(4.88414705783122,6.71635618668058,7.46116407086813));
#1075=CARTESIAN_POINT('',(4.89933297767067,6.743544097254,7.45070856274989));
#1076=CARTESIAN_POINT('',(4.90624477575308,6.75746853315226,7.44533772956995));
#1077=CARTESIAN_POINT('',(4.92545351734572,6.79995897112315,7.42889595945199));
#1078=CARTESIAN_POINT('',(4.93615332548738,6.82913157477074,7.41753794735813));
#1079=CARTESIAN_POINT('',(4.95513725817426,6.88986116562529,7.39373693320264));
#1080=CARTESIAN_POINT('',(4.96324824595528,6.92145910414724,7.38126902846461));
#1081=CARTESIAN_POINT('',(4.97688018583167,6.98510727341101,7.35597970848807));
#1082=CARTESIAN_POINT('',(4.98239809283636,7.01715799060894,7.34315789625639));
#1083=CARTESIAN_POINT('',(4.9911561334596,7.08135331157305,7.3172989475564));
#1084=CARTESIAN_POINT('',(4.99440347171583,7.11349729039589,7.30426262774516));
#1085=CARTESIAN_POINT('',(4.99878493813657,7.17784430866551,7.27798816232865));
#1086=CARTESIAN_POINT('',(4.99991944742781,7.21004733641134,7.26475005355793));
#1087=CARTESIAN_POINT('',(4.99999861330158,7.24337162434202,7.25095911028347));
#1088=CARTESIAN_POINT('',(4.9999999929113,7.24453002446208,7.25047960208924));
#1089=CARTESIAN_POINT('',(5.,7.24568837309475,7.24999999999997));
#1090=B_SPLINE_CURVE_WITH_KNOTS('',3,(#1060,#1061,#1062,#1063,#1064,#1065,#1066,#1067,#1068,
#1069,#1070,#1071,#1072,#1073,#1074,#1075,#1076,#1077,#1078,#1079,#1080,#1081,#1082,#1083,#1084,
#1085,#1086,#1087,#1088,#1089),.UNSPECIFIED.,.F.,.F.,(4,2,2,2,2,2,2,2,2,2,2,2,2,2,4),(0.,
0.0169451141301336,0.0336615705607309,0.0546483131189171,0.0757554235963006,0.111739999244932,
0.147802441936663,0.197002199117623,0.246298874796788,0.345301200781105,0.449965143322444,
0.554751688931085,0.659204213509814,0.763637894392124,0.767399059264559),.UNSPECIFIED.);
#1091=EDGE_CURVE('E376',#661,#47,#1090,.F.);
#1092=ORIENTED_EDGE('',*,*,#1091,.F.);
#1093=ORIENTED_EDGE('',*,*,#662,.F.);
#1094=EDGE_LOOP('',(#1058,#1059,#1092,#1093));
#1095=FACE_BOUND('',#1094,.T.);
#1096=ADVANCED_FACE('F366',(#1095),#1057,.T.);
#1097=CARTESIAN_POINT('',(4.75,0.,0.));
#1098=DIRECTION('',(-1.,0.,0.));
#1099=DIRECTION('',(0.,-1.,0.));
#1100=AXIS2_PLACEMENT_3D('',#1097,#1098,#1099);
#1101=TOROIDAL_SURFACE('',#1100,10.25,0.25);
#1102=ORIENTED_EDGE('',*,*,#1047,.T.);
#1103=ORIENTED_EDGE('',*,*,#671,.F.);
#1104=ORIENTED_EDGE('',*,*,#1091,.T.);
#1105=ORIENTED_EDGE('',*,*,#512,.F.);
#1106=EDGE_LOOP('',(#1102,#1103,#1104,#1105));
#1107=FACE_BOUND('',#1106,.T.);
#1108=ADVANCED_FACE('F371',(#1107),#1101,.T.);
#1109=CLOSED_SHELL('',(#226,#434,#457,#474,#492,#516,#540,#558,#582,#606,#630,#648,#690,#732,
#744,#756,#768,#780,#844,#888,#932,#944,#1008,#1052,#1096,#1108));
#1110=MANIFOLD_SOLID_BREP('B2',#1109);
#1111=ADVANCED_BREP_SHAPE_REPRESENTATION('',(#18,#1110),#14);
#1112=SHAPE_DEFINITION_REPRESENTATION(#9,#1111);
ENDSEC;
END-ISO-10303-21;
